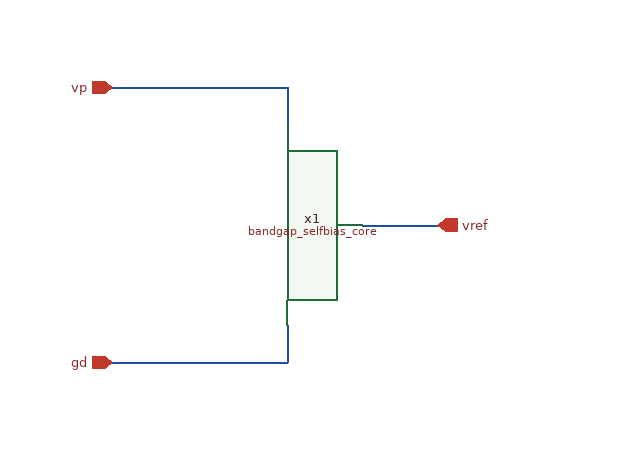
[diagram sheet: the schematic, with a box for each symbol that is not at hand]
v {xschem version=3.4.8RC file_version=1.3}
G {}
K {}
V {}
S {}
F {}
E {}
N 200 -120 260 -120 {lab=vref}
N 0 -230 140 -230 {lab=vp}
N 0 -10 140 -10 {lab=gd}
N 140 -40 140 -10 {lab=gd}
N 140 -230 140 -200 {lab=vp}
C {ipin.sym} 0 -10 0 0 {name=p13 lab=gd}
C {ipin.sym} 0 -230 0 0 {name=p14 lab=vp}
C {opin.sym} 260 -120 0 0 {name=p10 lab=vref}
C {/foss/designs/test/circuit/bandgap_selfbias_core.sym} 0 -120 0 0 {name=x1}
